VERSION 5.7 ;
  NOWIREEXTENSIONATPIN ON ;
  DIVIDERCHAR "/" ;
  BUSBITCHARS "[]" ;
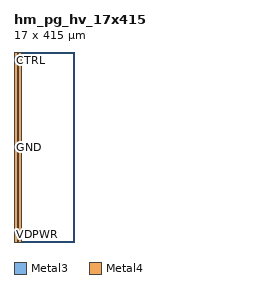
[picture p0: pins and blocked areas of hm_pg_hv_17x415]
MACRO hm_pg_hv_17x415
  CLASS BLOCK ;
  FOREIGN hm_pg_hv_17x415 ;
  ORIGIN 0.000 0.000 ;
  SIZE 17.000 BY 415.000 ;
  PIN CTRL
    DIRECTION INPUT ;
    USE SIGNAL ;
    ANTENNAGATEAREA 0.390000 ;
    PORT
      LAYER Metal3 ;
        RECT 0.000 414.500 17.000 415.000 ;
    END
  END CTRL
  PIN VAPWR
    DIRECTION INOUT ;
    USE POWER ;
    PORT
      LAYER Metal4 ;
        RECT 0.000 0.000 7.000 415.000 ;
    END
  END VAPWR
  PIN GND
    DIRECTION INOUT ;
    USE GROUND ;
    PORT
      LAYER Metal4 ;
        RECT 7.320 0.000 8.340 415.000 ;
    END
  END GND
  PIN VDPWR
    DIRECTION INOUT ;
    USE POWER ;
    PORT
      LAYER Metal4 ;
        RECT 8.660 0.000 9.680 415.000 ;
    END
  END VDPWR
  PIN GPWR
    DIRECTION INOUT ;
    USE POWER ;
    PORT
      LAYER Metal4 ;
        RECT 10.000 0.000 17.000 415.000 ;
    END
  END GPWR
  OBS
      LAYER GatPoly ;
        RECT 0.030 0.240 16.700 412.720 ;
      LAYER Metal1 ;
        RECT 0.000 0.240 16.700 413.230 ;
      LAYER Metal2 ;
        RECT 0.000 0.000 15.850 415.000 ;
      LAYER Metal3 ;
        RECT 0.000 0.000 17.000 412.520 ;
  END
END hm_pg_hv_17x415
END LIBRARY

